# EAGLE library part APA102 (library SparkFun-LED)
APA102 Addressable RGB LED Used in manufacturing of various products at SparkFun Packages: 5050 2020 SparkFun Products: SparkFun Lumenati Boards

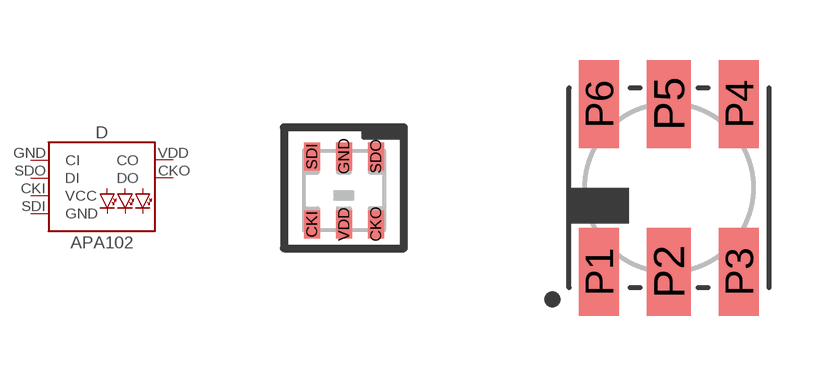
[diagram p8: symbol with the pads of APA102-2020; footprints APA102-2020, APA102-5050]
Designator prefix D

## APA102-2020 (PROD_ID: DIO-13883)  [APA102-2020]
CKI  VCC
CKO  DO
GND  CI
SDI  GND
SDO  DI
VDD  CO

## APA102-5050 (PROD_ID: DIO-13739)  [APA102-5050]
P1  DI
P2  CI
P3  GND
P4  VCC
P5  CO
P6  DO

## Footprint APA102-2020 (pad centres in mm)
APA102-2020 Specifications: Pin count: 8 Size: 2.0 x 2.0 mm Datasheet referenced for footprint: APA102-2020
smd 0.4 x 0.7: CKI -0.8,-0.85; CKO 0.8,-0.85; GND 0,0.85; SDI -0.8,0.85; SDO 0.8,0.85; VDD 0,-0.85

## Footprint APA102-5050 (pad centres in mm)
APA102C Specifications: Pin count: 6 Size: 5.0 x 5.0 mm Datasheet referenced for footprint: APA102C
smd 1 x 2.2: P1 -1.75,-2.1; P3 1.75,-2.1; P4 1.75,2.1; P6 -1.75,2.1
smd 1.1 x 2.2: P2 0,-2.1; P5 0,2.1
